VERSION 5.7 ;
  NOWIREEXTENSIONATPIN ON ;
  DIVIDERCHAR "/" ;
  BUSBITCHARS "[]" ;
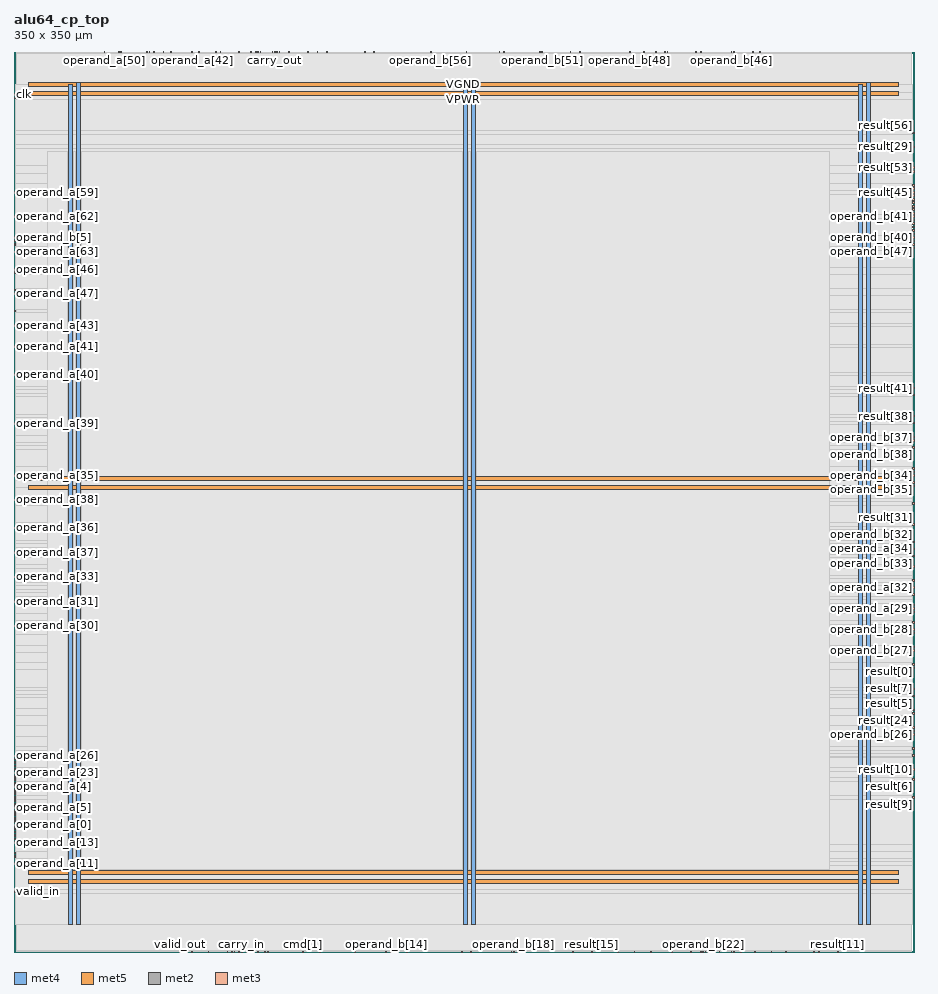
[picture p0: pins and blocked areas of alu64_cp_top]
MACRO alu64_cp_top
  CLASS BLOCK ;
  FOREIGN alu64_cp_top ;
  ORIGIN 0.000 0.000 ;
  SIZE 350.000 BY 350.000 ;
  PIN VGND
    DIRECTION INOUT ;
    USE GROUND ;
    PORT
      LAYER met4 ;
        RECT 24.340 10.640 25.940 337.990 ;
    END
    PORT
      LAYER met4 ;
        RECT 177.940 10.640 179.540 337.990 ;
    END
    PORT
      LAYER met4 ;
        RECT 331.540 10.640 333.140 337.990 ;
    END
    PORT
      LAYER met5 ;
        RECT 5.520 30.030 344.080 31.630 ;
    END
    PORT
      LAYER met5 ;
        RECT 5.520 183.210 344.080 184.810 ;
    END
    PORT
      LAYER met5 ;
        RECT 5.520 336.390 344.080 337.990 ;
    END
  END VGND
  PIN VPWR
    DIRECTION INOUT ;
    USE POWER ;
    PORT
      LAYER met4 ;
        RECT 21.040 10.640 22.640 337.520 ;
    END
    PORT
      LAYER met4 ;
        RECT 174.640 10.640 176.240 337.520 ;
    END
    PORT
      LAYER met4 ;
        RECT 328.240 10.640 329.840 337.520 ;
    END
    PORT
      LAYER met5 ;
        RECT 5.520 26.730 344.080 28.330 ;
    END
    PORT
      LAYER met5 ;
        RECT 5.520 179.910 344.080 181.510 ;
    END
    PORT
      LAYER met5 ;
        RECT 5.520 333.090 344.080 334.690 ;
    END
  END VPWR
  PIN carry_in
    DIRECTION INPUT ;
    USE SIGNAL ;
    ANTENNAGATEAREA 0.213000 ;
    PORT
      LAYER met2 ;
        RECT 88.410 0.000 88.690 0.280 ;
    END
  END carry_in
  PIN carry_out
    DIRECTION OUTPUT ;
    USE SIGNAL ;
    ANTENNADIFFAREA 0.702900 ;
    PORT
      LAYER met2 ;
        RECT 101.290 349.720 101.570 350.000 ;
    END
  END carry_out
  PIN clk
    DIRECTION INPUT ;
    USE SIGNAL ;
    ANTENNAGATEAREA 0.852000 ;
    PORT
      LAYER met3 ;
        RECT 0.000 333.240 0.600 333.840 ;
    END
  END clk
  PIN cmd[0]
    DIRECTION INPUT ;
    USE SIGNAL ;
    ANTENNAGATEAREA 0.213000 ;
    PORT
      LAYER met2 ;
        RECT 97.610 0.000 97.890 0.280 ;
    END
  END cmd[0]
  PIN cmd[1]
    DIRECTION INPUT ;
    USE SIGNAL ;
    ANTENNAGATEAREA 0.213000 ;
    PORT
      LAYER met2 ;
        RECT 112.330 0.000 112.610 0.280 ;
    END
  END cmd[1]
  PIN cmd[2]
    DIRECTION INPUT ;
    USE SIGNAL ;
    ANTENNAGATEAREA 0.213000 ;
    PORT
      LAYER met2 ;
        RECT 100.370 349.720 100.650 350.000 ;
    END
  END cmd[2]
  PIN cmd[3]
    DIRECTION INPUT ;
    USE SIGNAL ;
    ANTENNAGATEAREA 0.213000 ;
    PORT
      LAYER met2 ;
        RECT 93.930 349.720 94.210 350.000 ;
    END
  END cmd[3]
  PIN negative_flag
    DIRECTION OUTPUT ;
    USE SIGNAL ;
    ANTENNADIFFAREA 0.702900 ;
    PORT
      LAYER met3 ;
        RECT 349.400 296.520 350.000 297.120 ;
    END
  END negative_flag
  PIN operand_a[0]
    DIRECTION INPUT ;
    USE SIGNAL ;
    ANTENNAGATEAREA 0.213000 ;
    PORT
      LAYER met3 ;
        RECT 0.000 46.280 0.600 46.880 ;
    END
  END operand_a[0]
  PIN operand_a[10]
    DIRECTION INPUT ;
    USE SIGNAL ;
    ANTENNAGATEAREA 0.213000 ;
    PORT
      LAYER met3 ;
        RECT 0.000 51.720 0.600 52.320 ;
    END
  END operand_a[10]
  PIN operand_a[11]
    DIRECTION INPUT ;
    USE SIGNAL ;
    ANTENNAGATEAREA 0.213000 ;
    PORT
      LAYER met3 ;
        RECT 0.000 36.760 0.600 37.360 ;
    END
  END operand_a[11]
  PIN operand_a[12]
    DIRECTION INPUT ;
    USE SIGNAL ;
    ANTENNAGATEAREA 0.213000 ;
    PORT
      LAYER met3 ;
        RECT 0.000 34.040 0.600 34.640 ;
    END
  END operand_a[12]
  PIN operand_a[13]
    DIRECTION INPUT ;
    USE SIGNAL ;
    ANTENNAGATEAREA 0.213000 ;
    PORT
      LAYER met3 ;
        RECT 0.000 42.200 0.600 42.800 ;
    END
  END operand_a[13]
  PIN operand_a[14]
    DIRECTION INPUT ;
    USE SIGNAL ;
    ANTENNAGATEAREA 0.213000 ;
    PORT
      LAYER met3 ;
        RECT 0.000 54.440 0.600 55.040 ;
    END
  END operand_a[14]
  PIN operand_a[15]
    DIRECTION INPUT ;
    USE SIGNAL ;
    ANTENNAGATEAREA 0.213000 ;
    PORT
      LAYER met3 ;
        RECT 0.000 57.160 0.600 57.760 ;
    END
  END operand_a[15]
  PIN operand_a[16]
    DIRECTION INPUT ;
    USE SIGNAL ;
    ANTENNAGATEAREA 0.213000 ;
    PORT
      LAYER met3 ;
        RECT 0.000 38.120 0.600 38.720 ;
    END
  END operand_a[16]
  PIN operand_a[17]
    DIRECTION INPUT ;
    USE SIGNAL ;
    ANTENNAGATEAREA 0.213000 ;
    PORT
      LAYER met3 ;
        RECT 0.000 49.000 0.600 49.600 ;
    END
  END operand_a[17]
  PIN operand_a[18]
    DIRECTION INPUT ;
    USE SIGNAL ;
    ANTENNAGATEAREA 0.213000 ;
    PORT
      LAYER met3 ;
        RECT 0.000 53.080 0.600 53.680 ;
    END
  END operand_a[18]
  PIN operand_a[19]
    DIRECTION INPUT ;
    USE SIGNAL ;
    ANTENNAGATEAREA 0.213000 ;
    PORT
      LAYER met3 ;
        RECT 0.000 43.560 0.600 44.160 ;
    END
  END operand_a[19]
  PIN operand_a[1]
    DIRECTION INPUT ;
    USE SIGNAL ;
    ANTENNAGATEAREA 0.213000 ;
    PORT
      LAYER met2 ;
        RECT 69.090 0.000 69.370 0.280 ;
    END
  END operand_a[1]
  PIN operand_a[20]
    DIRECTION INPUT ;
    USE SIGNAL ;
    ANTENNAGATEAREA 0.213000 ;
    PORT
      LAYER met3 ;
        RECT 0.000 44.920 0.600 45.520 ;
    END
  END operand_a[20]
  PIN operand_a[21]
    DIRECTION INPUT ;
    USE SIGNAL ;
    ANTENNAGATEAREA 0.213000 ;
    PORT
      LAYER met3 ;
        RECT 0.000 61.240 0.600 61.840 ;
    END
  END operand_a[21]
  PIN operand_a[22]
    DIRECTION INPUT ;
    USE SIGNAL ;
    ANTENNAGATEAREA 0.213000 ;
    PORT
      LAYER met3 ;
        RECT 0.000 63.960 0.600 64.560 ;
    END
  END operand_a[22]
  PIN operand_a[23]
    DIRECTION INPUT ;
    USE SIGNAL ;
    ANTENNAGATEAREA 0.213000 ;
    PORT
      LAYER met3 ;
        RECT 0.000 69.400 0.600 70.000 ;
    END
  END operand_a[23]
  PIN operand_a[24]
    DIRECTION INPUT ;
    USE SIGNAL ;
    ANTENNAGATEAREA 0.213000 ;
    PORT
      LAYER met3 ;
        RECT 0.000 70.760 0.600 71.360 ;
    END
  END operand_a[24]
  PIN operand_a[25]
    DIRECTION INPUT ;
    USE SIGNAL ;
    ANTENNAGATEAREA 0.213000 ;
    PORT
      LAYER met2 ;
        RECT 75.530 0.000 75.810 0.280 ;
    END
  END operand_a[25]
  PIN operand_a[26]
    DIRECTION INPUT ;
    USE SIGNAL ;
    ANTENNAGATEAREA 0.213000 ;
    PORT
      LAYER met3 ;
        RECT 0.000 73.480 0.600 74.080 ;
    END
  END operand_a[26]
  PIN operand_a[27]
    DIRECTION INPUT ;
    USE SIGNAL ;
    ANTENNAGATEAREA 0.213000 ;
    PORT
      LAYER met3 ;
        RECT 0.000 47.640 0.600 48.240 ;
    END
  END operand_a[27]
  PIN operand_a[28]
    DIRECTION INPUT ;
    USE SIGNAL ;
    ANTENNAGATEAREA 0.213000 ;
    PORT
      LAYER met3 ;
        RECT 0.000 74.840 0.600 75.440 ;
    END
  END operand_a[28]
  PIN operand_a[29]
    DIRECTION INPUT ;
    USE SIGNAL ;
    ANTENNAGATEAREA 0.213000 ;
    PORT
      LAYER met3 ;
        RECT 349.400 133.320 350.000 133.920 ;
    END
  END operand_a[29]
  PIN operand_a[2]
    DIRECTION INPUT ;
    USE SIGNAL ;
    ANTENNAGATEAREA 0.213000 ;
    PORT
      LAYER met3 ;
        RECT 0.000 68.040 0.600 68.640 ;
    END
  END operand_a[2]
  PIN operand_a[30]
    DIRECTION INPUT ;
    USE SIGNAL ;
    ANTENNAGATEAREA 0.213000 ;
    PORT
      LAYER met3 ;
        RECT 0.000 126.520 0.600 127.120 ;
    END
  END operand_a[30]
  PIN operand_a[31]
    DIRECTION INPUT ;
    USE SIGNAL ;
    ANTENNAGATEAREA 0.213000 ;
    PORT
      LAYER met3 ;
        RECT 0.000 136.040 0.600 136.640 ;
    END
  END operand_a[31]
  PIN operand_a[32]
    DIRECTION INPUT ;
    USE SIGNAL ;
    ANTENNAGATEAREA 0.213000 ;
    PORT
      LAYER met3 ;
        RECT 349.400 141.480 350.000 142.080 ;
    END
  END operand_a[32]
  PIN operand_a[33]
    DIRECTION INPUT ;
    USE SIGNAL ;
    ANTENNAGATEAREA 0.213000 ;
    PORT
      LAYER met3 ;
        RECT 0.000 145.560 0.600 146.160 ;
    END
  END operand_a[33]
  PIN operand_a[34]
    DIRECTION INPUT ;
    USE SIGNAL ;
    ANTENNAGATEAREA 0.213000 ;
    PORT
      LAYER met3 ;
        RECT 349.400 156.440 350.000 157.040 ;
    END
  END operand_a[34]
  PIN operand_a[35]
    DIRECTION INPUT ;
    USE SIGNAL ;
    ANTENNAGATEAREA 0.213000 ;
    PORT
      LAYER met3 ;
        RECT 0.000 185.000 0.600 185.600 ;
    END
  END operand_a[35]
  PIN operand_a[36]
    DIRECTION INPUT ;
    USE SIGNAL ;
    ANTENNAGATEAREA 0.213000 ;
    PORT
      LAYER met3 ;
        RECT 0.000 164.600 0.600 165.200 ;
    END
  END operand_a[36]
  PIN operand_a[37]
    DIRECTION INPUT ;
    USE SIGNAL ;
    ANTENNAGATEAREA 0.213000 ;
    PORT
      LAYER met3 ;
        RECT 0.000 155.080 0.600 155.680 ;
    END
  END operand_a[37]
  PIN operand_a[38]
    DIRECTION INPUT ;
    USE SIGNAL ;
    ANTENNAGATEAREA 0.213000 ;
    PORT
      LAYER met3 ;
        RECT 0.000 175.480 0.600 176.080 ;
    END
  END operand_a[38]
  PIN operand_a[39]
    DIRECTION INPUT ;
    USE SIGNAL ;
    ANTENNAGATEAREA 0.213000 ;
    PORT
      LAYER met3 ;
        RECT 0.000 205.400 0.600 206.000 ;
    END
  END operand_a[39]
  PIN operand_a[3]
    DIRECTION INPUT ;
    USE SIGNAL ;
    ANTENNAGATEAREA 0.213000 ;
    PORT
      LAYER met3 ;
        RECT 0.000 72.120 0.600 72.720 ;
    END
  END operand_a[3]
  PIN operand_a[40]
    DIRECTION INPUT ;
    USE SIGNAL ;
    ANTENNAGATEAREA 0.213000 ;
    PORT
      LAYER met3 ;
        RECT 0.000 224.440 0.600 225.040 ;
    END
  END operand_a[40]
  PIN operand_a[41]
    DIRECTION INPUT ;
    USE SIGNAL ;
    ANTENNAGATEAREA 0.213000 ;
    PORT
      LAYER met3 ;
        RECT 0.000 235.320 0.600 235.920 ;
    END
  END operand_a[41]
  PIN operand_a[42]
    DIRECTION INPUT ;
    USE SIGNAL ;
    ANTENNAGATEAREA 0.213000 ;
    PORT
      LAYER met2 ;
        RECT 69.090 349.720 69.370 350.000 ;
    END
  END operand_a[42]
  PIN operand_a[43]
    DIRECTION INPUT ;
    USE SIGNAL ;
    ANTENNAGATEAREA 0.213000 ;
    PORT
      LAYER met3 ;
        RECT 0.000 243.480 0.600 244.080 ;
    END
  END operand_a[43]
  PIN operand_a[44]
    DIRECTION INPUT ;
    USE SIGNAL ;
    ANTENNAGATEAREA 0.213000 ;
    PORT
      LAYER met2 ;
        RECT 58.050 349.720 58.330 350.000 ;
    END
  END operand_a[44]
  PIN operand_a[45]
    DIRECTION INPUT ;
    USE SIGNAL ;
    ANTENNAGATEAREA 0.213000 ;
    PORT
      LAYER met3 ;
        RECT 0.000 257.080 0.600 257.680 ;
    END
  END operand_a[45]
  PIN operand_a[46]
    DIRECTION INPUT ;
    USE SIGNAL ;
    ANTENNAGATEAREA 0.213000 ;
    PORT
      LAYER met3 ;
        RECT 0.000 265.240 0.600 265.840 ;
    END
  END operand_a[46]
  PIN operand_a[47]
    DIRECTION INPUT ;
    USE SIGNAL ;
    ANTENNAGATEAREA 0.213000 ;
    PORT
      LAYER met3 ;
        RECT 0.000 255.720 0.600 256.320 ;
    END
  END operand_a[47]
  PIN operand_a[48]
    DIRECTION INPUT ;
    USE SIGNAL ;
    ANTENNAGATEAREA 0.213000 ;
    PORT
      LAYER met2 ;
        RECT 60.810 349.720 61.090 350.000 ;
    END
  END operand_a[48]
  PIN operand_a[49]
    DIRECTION INPUT ;
    USE SIGNAL ;
    ANTENNAGATEAREA 0.213000 ;
    PORT
      LAYER met2 ;
        RECT 71.850 349.720 72.130 350.000 ;
    END
  END operand_a[49]
  PIN operand_a[4]
    DIRECTION INPUT ;
    USE SIGNAL ;
    ANTENNAGATEAREA 0.213000 ;
    PORT
      LAYER met3 ;
        RECT 0.000 66.680 0.600 67.280 ;
    END
  END operand_a[4]
  PIN operand_a[50]
    DIRECTION INPUT ;
    USE SIGNAL ;
    ANTENNAGATEAREA 0.213000 ;
    PORT
      LAYER met2 ;
        RECT 35.050 349.720 35.330 350.000 ;
    END
  END operand_a[50]
  PIN operand_a[51]
    DIRECTION INPUT ;
    USE SIGNAL ;
    ANTENNAGATEAREA 0.213000 ;
    PORT
      LAYER met2 ;
        RECT 52.530 349.720 52.810 350.000 ;
    END
  END operand_a[51]
  PIN operand_a[52]
    DIRECTION INPUT ;
    USE SIGNAL ;
    ANTENNAGATEAREA 0.213000 ;
    PORT
      LAYER met2 ;
        RECT 41.490 349.720 41.770 350.000 ;
    END
  END operand_a[52]
  PIN operand_a[53]
    DIRECTION INPUT ;
    USE SIGNAL ;
    ANTENNAGATEAREA 0.213000 ;
    PORT
      LAYER met2 ;
        RECT 80.130 349.720 80.410 350.000 ;
    END
  END operand_a[53]
  PIN operand_a[54]
    DIRECTION INPUT ;
    USE SIGNAL ;
    ANTENNAGATEAREA 0.213000 ;
    PORT
      LAYER met2 ;
        RECT 87.490 349.720 87.770 350.000 ;
    END
  END operand_a[54]
  PIN operand_a[55]
    DIRECTION INPUT ;
    USE SIGNAL ;
    ANTENNAGATEAREA 0.213000 ;
    PORT
      LAYER met2 ;
        RECT 78.290 349.720 78.570 350.000 ;
    END
  END operand_a[55]
  PIN operand_a[56]
    DIRECTION INPUT ;
    USE SIGNAL ;
    ANTENNAGATEAREA 0.213000 ;
    PORT
      LAYER met2 ;
        RECT 95.770 349.720 96.050 350.000 ;
    END
  END operand_a[56]
  PIN operand_a[57]
    DIRECTION INPUT ;
    USE SIGNAL ;
    ANTENNAGATEAREA 0.213000 ;
    PORT
      LAYER met2 ;
        RECT 92.090 349.720 92.370 350.000 ;
    END
  END operand_a[57]
  PIN operand_a[58]
    DIRECTION INPUT ;
    USE SIGNAL ;
    ANTENNAGATEAREA 0.213000 ;
    PORT
      LAYER met2 ;
        RECT 94.850 349.720 95.130 350.000 ;
    END
  END operand_a[58]
  PIN operand_a[59]
    DIRECTION INPUT ;
    USE SIGNAL ;
    ANTENNAGATEAREA 0.213000 ;
    PORT
      LAYER met3 ;
        RECT 0.000 295.160 0.600 295.760 ;
    END
  END operand_a[59]
  PIN operand_a[5]
    DIRECTION INPUT ;
    USE SIGNAL ;
    ANTENNAGATEAREA 0.213000 ;
    PORT
      LAYER met3 ;
        RECT 0.000 58.520 0.600 59.120 ;
    END
  END operand_a[5]
  PIN operand_a[60]
    DIRECTION INPUT ;
    USE SIGNAL ;
    ANTENNAGATEAREA 0.213000 ;
    PORT
      LAYER met2 ;
        RECT 54.370 349.720 54.650 350.000 ;
    END
  END operand_a[60]
  PIN operand_a[61]
    DIRECTION INPUT ;
    USE SIGNAL ;
    ANTENNAGATEAREA 0.213000 ;
    PORT
      LAYER met2 ;
        RECT 51.610 349.720 51.890 350.000 ;
    END
  END operand_a[61]
  PIN operand_a[62]
    DIRECTION INPUT ;
    USE SIGNAL ;
    ANTENNAGATEAREA 0.213000 ;
    PORT
      LAYER met3 ;
        RECT 0.000 285.640 0.600 286.240 ;
    END
  END operand_a[62]
  PIN operand_a[63]
    DIRECTION INPUT ;
    USE SIGNAL ;
    ANTENNAGATEAREA 0.213000 ;
    PORT
      LAYER met3 ;
        RECT 0.000 274.760 0.600 275.360 ;
    END
  END operand_a[63]
  PIN operand_a[6]
    DIRECTION INPUT ;
    USE SIGNAL ;
    ANTENNAGATEAREA 0.213000 ;
    PORT
      LAYER met3 ;
        RECT 0.000 65.320 0.600 65.920 ;
    END
  END operand_a[6]
  PIN operand_a[7]
    DIRECTION INPUT ;
    USE SIGNAL ;
    ANTENNAGATEAREA 0.213000 ;
    PORT
      LAYER met3 ;
        RECT 0.000 50.360 0.600 50.960 ;
    END
  END operand_a[7]
  PIN operand_a[8]
    DIRECTION INPUT ;
    USE SIGNAL ;
    ANTENNAGATEAREA 0.213000 ;
    PORT
      LAYER met3 ;
        RECT 0.000 59.880 0.600 60.480 ;
    END
  END operand_a[8]
  PIN operand_a[9]
    DIRECTION INPUT ;
    USE SIGNAL ;
    ANTENNAGATEAREA 0.213000 ;
    PORT
      LAYER met3 ;
        RECT 0.000 62.600 0.600 63.200 ;
    END
  END operand_a[9]
  PIN operand_b[0]
    DIRECTION INPUT ;
    USE SIGNAL ;
    ANTENNAGATEAREA 0.213000 ;
    PORT
      LAYER met3 ;
        RECT 0.000 55.800 0.600 56.400 ;
    END
  END operand_b[0]
  PIN operand_b[10]
    DIRECTION INPUT ;
    USE SIGNAL ;
    ANTENNAGATEAREA 0.213000 ;
    PORT
      LAYER met2 ;
        RECT 98.530 0.000 98.810 0.280 ;
    END
  END operand_b[10]
  PIN operand_b[11]
    DIRECTION INPUT ;
    USE SIGNAL ;
    ANTENNAGATEAREA 0.213000 ;
    PORT
      LAYER met2 ;
        RECT 94.850 0.000 95.130 0.280 ;
    END
  END operand_b[11]
  PIN operand_b[12]
    DIRECTION INPUT ;
    USE SIGNAL ;
    ANTENNAGATEAREA 0.213000 ;
    PORT
      LAYER met2 ;
        RECT 118.770 0.000 119.050 0.280 ;
    END
  END operand_b[12]
  PIN operand_b[13]
    DIRECTION INPUT ;
    USE SIGNAL ;
    ANTENNAGATEAREA 0.213000 ;
    PORT
      LAYER met2 ;
        RECT 132.570 0.000 132.850 0.280 ;
    END
  END operand_b[13]
  PIN operand_b[14]
    DIRECTION INPUT ;
    USE SIGNAL ;
    ANTENNAGATEAREA 0.213000 ;
    PORT
      LAYER met2 ;
        RECT 144.530 0.000 144.810 0.280 ;
    END
  END operand_b[14]
  PIN operand_b[15]
    DIRECTION INPUT ;
    USE SIGNAL ;
    ANTENNAGATEAREA 0.213000 ;
    PORT
      LAYER met2 ;
        RECT 149.130 0.000 149.410 0.280 ;
    END
  END operand_b[15]
  PIN operand_b[16]
    DIRECTION INPUT ;
    USE SIGNAL ;
    ANTENNAGATEAREA 0.213000 ;
    PORT
      LAYER met2 ;
        RECT 152.810 0.000 153.090 0.280 ;
    END
  END operand_b[16]
  PIN operand_b[17]
    DIRECTION INPUT ;
    USE SIGNAL ;
    ANTENNAGATEAREA 0.213000 ;
    PORT
      LAYER met2 ;
        RECT 173.970 0.000 174.250 0.280 ;
    END
  END operand_b[17]
  PIN operand_b[18]
    DIRECTION INPUT ;
    USE SIGNAL ;
    ANTENNAGATEAREA 0.213000 ;
    PORT
      LAYER met2 ;
        RECT 194.210 0.000 194.490 0.280 ;
    END
  END operand_b[18]
  PIN operand_b[19]
    DIRECTION INPUT ;
    USE SIGNAL ;
    ANTENNAGATEAREA 0.213000 ;
    PORT
      LAYER met2 ;
        RECT 217.210 0.000 217.490 0.280 ;
    END
  END operand_b[19]
  PIN operand_b[1]
    DIRECTION INPUT ;
    USE SIGNAL ;
    ANTENNAGATEAREA 0.213000 ;
    PORT
      LAYER met3 ;
        RECT 0.000 263.880 0.600 264.480 ;
    END
  END operand_b[1]
  PIN operand_b[20]
    DIRECTION INPUT ;
    USE SIGNAL ;
    ANTENNAGATEAREA 0.213000 ;
    PORT
      LAYER met2 ;
        RECT 241.130 0.000 241.410 0.280 ;
    END
  END operand_b[20]
  PIN operand_b[21]
    DIRECTION INPUT ;
    USE SIGNAL ;
    ANTENNAGATEAREA 0.213000 ;
    PORT
      LAYER met2 ;
        RECT 255.850 0.000 256.130 0.280 ;
    END
  END operand_b[21]
  PIN operand_b[22]
    DIRECTION INPUT ;
    USE SIGNAL ;
    ANTENNAGATEAREA 0.213000 ;
    PORT
      LAYER met2 ;
        RECT 267.810 0.000 268.090 0.280 ;
    END
  END operand_b[22]
  PIN operand_b[23]
    DIRECTION INPUT ;
    USE SIGNAL ;
    ANTENNAGATEAREA 0.213000 ;
    PORT
      LAYER met2 ;
        RECT 278.850 0.000 279.130 0.280 ;
    END
  END operand_b[23]
  PIN operand_b[24]
    DIRECTION INPUT ;
    USE SIGNAL ;
    ANTENNAGATEAREA 0.213000 ;
    PORT
      LAYER met2 ;
        RECT 282.530 0.000 282.810 0.280 ;
    END
  END operand_b[24]
  PIN operand_b[25]
    DIRECTION INPUT ;
    USE SIGNAL ;
    ANTENNAGATEAREA 0.213000 ;
    PORT
      LAYER met2 ;
        RECT 274.250 0.000 274.530 0.280 ;
    END
  END operand_b[25]
  PIN operand_b[26]
    DIRECTION INPUT ;
    USE SIGNAL ;
    ANTENNAGATEAREA 0.213000 ;
    PORT
      LAYER met3 ;
        RECT 349.400 84.360 350.000 84.960 ;
    END
  END operand_b[26]
  PIN operand_b[27]
    DIRECTION INPUT ;
    USE SIGNAL ;
    ANTENNAGATEAREA 0.213000 ;
    PORT
      LAYER met3 ;
        RECT 349.400 117.000 350.000 117.600 ;
    END
  END operand_b[27]
  PIN operand_b[28]
    DIRECTION INPUT ;
    USE SIGNAL ;
    ANTENNAGATEAREA 0.213000 ;
    PORT
      LAYER met3 ;
        RECT 349.400 127.880 350.000 128.480 ;
    END
  END operand_b[28]
  PIN operand_b[29]
    DIRECTION INPUT ;
    USE SIGNAL ;
    ANTENNAGATEAREA 0.213000 ;
    PORT
      LAYER met3 ;
        RECT 349.400 131.960 350.000 132.560 ;
    END
  END operand_b[29]
  PIN operand_b[2]
    DIRECTION INPUT ;
    USE SIGNAL ;
    ANTENNAGATEAREA 0.213000 ;
    PORT
      LAYER met3 ;
        RECT 0.000 276.120 0.600 276.720 ;
    END
  END operand_b[2]
  PIN operand_b[30]
    DIRECTION INPUT ;
    USE SIGNAL ;
    ANTENNAGATEAREA 0.213000 ;
    PORT
      LAYER met3 ;
        RECT 349.400 123.800 350.000 124.400 ;
    END
  END operand_b[30]
  PIN operand_b[31]
    DIRECTION INPUT ;
    USE SIGNAL ;
    ANTENNAGATEAREA 0.213000 ;
    PORT
      LAYER met3 ;
        RECT 349.400 134.680 350.000 135.280 ;
    END
  END operand_b[31]
  PIN operand_b[32]
    DIRECTION INPUT ;
    USE SIGNAL ;
    ANTENNAGATEAREA 0.213000 ;
    PORT
      LAYER met3 ;
        RECT 349.400 159.160 350.000 159.760 ;
    END
  END operand_b[32]
  PIN operand_b[33]
    DIRECTION INPUT ;
    USE SIGNAL ;
    ANTENNAGATEAREA 0.213000 ;
    PORT
      LAYER met3 ;
        RECT 349.400 153.720 350.000 154.320 ;
    END
  END operand_b[33]
  PIN operand_b[34]
    DIRECTION INPUT ;
    USE SIGNAL ;
    ANTENNAGATEAREA 0.213000 ;
    PORT
      LAYER met3 ;
        RECT 349.400 185.000 350.000 185.600 ;
    END
  END operand_b[34]
  PIN operand_b[35]
    DIRECTION INPUT ;
    USE SIGNAL ;
    ANTENNAGATEAREA 0.213000 ;
    PORT
      LAYER met3 ;
        RECT 349.400 182.280 350.000 182.880 ;
    END
  END operand_b[35]
  PIN operand_b[36]
    DIRECTION INPUT ;
    USE SIGNAL ;
    ANTENNAGATEAREA 0.213000 ;
    PORT
      LAYER met3 ;
        RECT 349.400 186.360 350.000 186.960 ;
    END
  END operand_b[36]
  PIN operand_b[37]
    DIRECTION INPUT ;
    USE SIGNAL ;
    ANTENNAGATEAREA 0.213000 ;
    PORT
      LAYER met3 ;
        RECT 349.400 199.960 350.000 200.560 ;
    END
  END operand_b[37]
  PIN operand_b[38]
    DIRECTION INPUT ;
    USE SIGNAL ;
    ANTENNAGATEAREA 0.213000 ;
    PORT
      LAYER met3 ;
        RECT 349.400 195.880 350.000 196.480 ;
    END
  END operand_b[38]
  PIN operand_b[39]
    DIRECTION INPUT ;
    USE SIGNAL ;
    ANTENNAGATEAREA 0.213000 ;
    PORT
      LAYER met3 ;
        RECT 349.400 187.720 350.000 188.320 ;
    END
  END operand_b[39]
  PIN operand_b[3]
    DIRECTION INPUT ;
    USE SIGNAL ;
    ANTENNAGATEAREA 0.213000 ;
    PORT
      LAYER met3 ;
        RECT 0.000 248.920 0.600 249.520 ;
    END
  END operand_b[3]
  PIN operand_b[40]
    DIRECTION INPUT ;
    USE SIGNAL ;
    ANTENNAGATEAREA 0.213000 ;
    PORT
      LAYER met3 ;
        RECT 349.400 277.480 350.000 278.080 ;
    END
  END operand_b[40]
  PIN operand_b[41]
    DIRECTION INPUT ;
    USE SIGNAL ;
    ANTENNAGATEAREA 0.213000 ;
    PORT
      LAYER met3 ;
        RECT 349.400 282.920 350.000 283.520 ;
    END
  END operand_b[41]
  PIN operand_b[42]
    DIRECTION INPUT ;
    USE SIGNAL ;
    ANTENNAGATEAREA 0.213000 ;
    PORT
      LAYER met3 ;
        RECT 349.400 276.120 350.000 276.720 ;
    END
  END operand_b[42]
  PIN operand_b[43]
    DIRECTION INPUT ;
    USE SIGNAL ;
    ANTENNAGATEAREA 0.213000 ;
    PORT
      LAYER met3 ;
        RECT 349.400 291.080 350.000 291.680 ;
    END
  END operand_b[43]
  PIN operand_b[44]
    DIRECTION INPUT ;
    USE SIGNAL ;
    ANTENNAGATEAREA 0.213000 ;
    PORT
      LAYER met3 ;
        RECT 349.400 292.440 350.000 293.040 ;
    END
  END operand_b[44]
  PIN operand_b[45]
    DIRECTION INPUT ;
    USE SIGNAL ;
    ANTENNAGATEAREA 0.213000 ;
    PORT
      LAYER met3 ;
        RECT 349.400 285.640 350.000 286.240 ;
    END
  END operand_b[45]
  PIN operand_b[46]
    DIRECTION INPUT ;
    USE SIGNAL ;
    ANTENNAGATEAREA 0.213000 ;
    PORT
      LAYER met2 ;
        RECT 278.850 349.720 279.130 350.000 ;
    END
  END operand_b[46]
  PIN operand_b[47]
    DIRECTION INPUT ;
    USE SIGNAL ;
    ANTENNAGATEAREA 0.213000 ;
    PORT
      LAYER met3 ;
        RECT 349.400 274.760 350.000 275.360 ;
    END
  END operand_b[47]
  PIN operand_b[48]
    DIRECTION INPUT ;
    USE SIGNAL ;
    ANTENNAGATEAREA 0.213000 ;
    PORT
      LAYER met2 ;
        RECT 239.290 349.720 239.570 350.000 ;
    END
  END operand_b[48]
  PIN operand_b[49]
    DIRECTION INPUT ;
    USE SIGNAL ;
    ANTENNAGATEAREA 0.213000 ;
    PORT
      LAYER met2 ;
        RECT 219.970 349.720 220.250 350.000 ;
    END
  END operand_b[49]
  PIN operand_b[4]
    DIRECTION INPUT ;
    USE SIGNAL ;
    ANTENNAGATEAREA 0.213000 ;
    PORT
      LAYER met2 ;
        RECT 40.570 349.720 40.850 350.000 ;
    END
  END operand_b[4]
  PIN operand_b[50]
    DIRECTION INPUT ;
    USE SIGNAL ;
    ANTENNAGATEAREA 0.213000 ;
    PORT
      LAYER met2 ;
        RECT 216.290 349.720 216.570 350.000 ;
    END
  END operand_b[50]
  PIN operand_b[51]
    DIRECTION INPUT ;
    USE SIGNAL ;
    ANTENNAGATEAREA 0.213000 ;
    PORT
      LAYER met2 ;
        RECT 205.250 349.720 205.530 350.000 ;
    END
  END operand_b[51]
  PIN operand_b[52]
    DIRECTION INPUT ;
    USE SIGNAL ;
    ANTENNAGATEAREA 0.213000 ;
    PORT
      LAYER met2 ;
        RECT 204.330 349.720 204.610 350.000 ;
    END
  END operand_b[52]
  PIN operand_b[53]
    DIRECTION INPUT ;
    USE SIGNAL ;
    ANTENNAGATEAREA 0.213000 ;
    PORT
      LAYER met2 ;
        RECT 188.690 349.720 188.970 350.000 ;
    END
  END operand_b[53]
  PIN operand_b[54]
    DIRECTION INPUT ;
    USE SIGNAL ;
    ANTENNAGATEAREA 0.213000 ;
    PORT
      LAYER met2 ;
        RECT 190.530 349.720 190.810 350.000 ;
    END
  END operand_b[54]
  PIN operand_b[55]
    DIRECTION INPUT ;
    USE SIGNAL ;
    ANTENNAGATEAREA 0.213000 ;
    PORT
      LAYER met2 ;
        RECT 175.810 349.720 176.090 350.000 ;
    END
  END operand_b[55]
  PIN operand_b[56]
    DIRECTION INPUT ;
    USE SIGNAL ;
    ANTENNAGATEAREA 0.213000 ;
    PORT
      LAYER met2 ;
        RECT 162.010 349.720 162.290 350.000 ;
    END
  END operand_b[56]
  PIN operand_b[57]
    DIRECTION INPUT ;
    USE SIGNAL ;
    ANTENNAGATEAREA 0.213000 ;
    PORT
      LAYER met2 ;
        RECT 139.930 349.720 140.210 350.000 ;
    END
  END operand_b[57]
  PIN operand_b[58]
    DIRECTION INPUT ;
    USE SIGNAL ;
    ANTENNAGATEAREA 0.213000 ;
    PORT
      LAYER met2 ;
        RECT 136.250 349.720 136.530 350.000 ;
    END
  END operand_b[58]
  PIN operand_b[59]
    DIRECTION INPUT ;
    USE SIGNAL ;
    ANTENNAGATEAREA 0.213000 ;
    PORT
      LAYER met2 ;
        RECT 117.850 349.720 118.130 350.000 ;
    END
  END operand_b[59]
  PIN operand_b[5]
    DIRECTION INPUT ;
    USE SIGNAL ;
    ANTENNAGATEAREA 0.213000 ;
    PORT
      LAYER met3 ;
        RECT 0.000 277.480 0.600 278.080 ;
    END
  END operand_b[5]
  PIN operand_b[60]
    DIRECTION INPUT ;
    USE SIGNAL ;
    ANTENNAGATEAREA 0.213000 ;
    PORT
      LAYER met2 ;
        RECT 114.170 349.720 114.450 350.000 ;
    END
  END operand_b[60]
  PIN operand_b[61]
    DIRECTION INPUT ;
    USE SIGNAL ;
    ANTENNAGATEAREA 0.213000 ;
    PORT
      LAYER met2 ;
        RECT 106.810 349.720 107.090 350.000 ;
    END
  END operand_b[61]
  PIN operand_b[62]
    DIRECTION INPUT ;
    USE SIGNAL ;
    ANTENNAGATEAREA 0.213000 ;
    PORT
      LAYER met2 ;
        RECT 103.130 349.720 103.410 350.000 ;
    END
  END operand_b[62]
  PIN operand_b[63]
    DIRECTION INPUT ;
    USE SIGNAL ;
    ANTENNAGATEAREA 0.213000 ;
    PORT
      LAYER met2 ;
        RECT 102.210 349.720 102.490 350.000 ;
    END
  END operand_b[63]
  PIN operand_b[6]
    DIRECTION INPUT ;
    USE SIGNAL ;
    ANTENNAGATEAREA 0.213000 ;
    PORT
      LAYER met2 ;
        RECT 82.890 0.000 83.170 0.280 ;
    END
  END operand_b[6]
  PIN operand_b[7]
    DIRECTION INPUT ;
    USE SIGNAL ;
    ANTENNAGATEAREA 0.213000 ;
    PORT
      LAYER met2 ;
        RECT 85.650 0.000 85.930 0.280 ;
    END
  END operand_b[7]
  PIN operand_b[8]
    DIRECTION INPUT ;
    USE SIGNAL ;
    ANTENNAGATEAREA 0.213000 ;
    PORT
      LAYER met2 ;
        RECT 84.730 0.000 85.010 0.280 ;
    END
  END operand_b[8]
  PIN operand_b[9]
    DIRECTION INPUT ;
    USE SIGNAL ;
    ANTENNAGATEAREA 0.213000 ;
    PORT
      LAYER met2 ;
        RECT 87.490 0.000 87.770 0.280 ;
    END
  END operand_b[9]
  PIN overflow_flag
    DIRECTION OUTPUT ;
    USE SIGNAL ;
    ANTENNADIFFAREA 0.702900 ;
    PORT
      LAYER met2 ;
        RECT 121.530 349.720 121.810 350.000 ;
    END
  END overflow_flag
  PIN result[0]
    DIRECTION OUTPUT ;
    USE SIGNAL ;
    ANTENNADIFFAREA 0.702900 ;
    PORT
      LAYER met3 ;
        RECT 349.400 111.560 350.000 112.160 ;
    END
  END result[0]
  PIN result[10]
    DIRECTION OUTPUT ;
    USE SIGNAL ;
    ANTENNADIFFAREA 0.702900 ;
    PORT
      LAYER met3 ;
        RECT 349.400 70.760 350.000 71.360 ;
    END
  END result[10]
  PIN result[11]
    DIRECTION OUTPUT ;
    USE SIGNAL ;
    ANTENNADIFFAREA 0.702900 ;
    PORT
      LAYER met2 ;
        RECT 320.250 0.000 320.530 0.280 ;
    END
  END result[11]
  PIN result[12]
    DIRECTION OUTPUT ;
    USE SIGNAL ;
    ANTENNADIFFAREA 0.702900 ;
    PORT
      LAYER met2 ;
        RECT 266.890 0.000 267.170 0.280 ;
    END
  END result[12]
  PIN result[13]
    DIRECTION OUTPUT ;
    USE SIGNAL ;
    ANTENNADIFFAREA 0.702900 ;
    PORT
      LAYER met2 ;
        RECT 311.050 0.000 311.330 0.280 ;
    END
  END result[13]
  PIN result[14]
    DIRECTION OUTPUT ;
    USE SIGNAL ;
    ANTENNADIFFAREA 0.702900 ;
    PORT
      LAYER met2 ;
        RECT 193.290 0.000 193.570 0.280 ;
    END
  END result[14]
  PIN result[15]
    DIRECTION OUTPUT ;
    USE SIGNAL ;
    ANTENNADIFFAREA 0.702900 ;
    PORT
      LAYER met2 ;
        RECT 224.570 0.000 224.850 0.280 ;
    END
  END result[15]
  PIN result[16]
    DIRECTION OUTPUT ;
    USE SIGNAL ;
    ANTENNADIFFAREA 0.702900 ;
    PORT
      LAYER met2 ;
        RECT 263.210 0.000 263.490 0.280 ;
    END
  END result[16]
  PIN result[17]
    DIRECTION OUTPUT ;
    USE SIGNAL ;
    ANTENNADIFFAREA 0.702900 ;
    PORT
      LAYER met2 ;
        RECT 234.690 0.000 234.970 0.280 ;
    END
  END result[17]
  PIN result[18]
    DIRECTION OUTPUT ;
    USE SIGNAL ;
    ANTENNADIFFAREA 0.702900 ;
    PORT
      LAYER met2 ;
        RECT 177.650 0.000 177.930 0.280 ;
    END
  END result[18]
  PIN result[19]
    DIRECTION OUTPUT ;
    USE SIGNAL ;
    ANTENNADIFFAREA 0.702900 ;
    PORT
      LAYER met2 ;
        RECT 247.570 0.000 247.850 0.280 ;
    END
  END result[19]
  PIN result[1]
    DIRECTION OUTPUT ;
    USE SIGNAL ;
    ANTENNADIFFAREA 0.702900 ;
    PORT
      LAYER met3 ;
        RECT 349.400 78.920 350.000 79.520 ;
    END
  END result[1]
  PIN result[20]
    DIRECTION OUTPUT ;
    USE SIGNAL ;
    ANTENNADIFFAREA 0.702900 ;
    PORT
      LAYER met2 ;
        RECT 288.050 0.000 288.330 0.280 ;
    END
  END result[20]
  PIN result[21]
    DIRECTION OUTPUT ;
    USE SIGNAL ;
    ANTENNADIFFAREA 0.702900 ;
    PORT
      LAYER met2 ;
        RECT 268.730 0.000 269.010 0.280 ;
    END
  END result[21]
  PIN result[22]
    DIRECTION OUTPUT ;
    USE SIGNAL ;
    ANTENNADIFFAREA 0.702900 ;
    PORT
      LAYER met2 ;
        RECT 294.490 0.000 294.770 0.280 ;
    END
  END result[22]
  PIN result[23]
    DIRECTION OUTPUT ;
    USE SIGNAL ;
    ANTENNADIFFAREA 0.702900 ;
    PORT
      LAYER met2 ;
        RECT 300.010 0.000 300.290 0.280 ;
    END
  END result[23]
  PIN result[24]
    DIRECTION OUTPUT ;
    USE SIGNAL ;
    ANTENNADIFFAREA 0.702900 ;
    PORT
      LAYER met3 ;
        RECT 349.400 87.080 350.000 87.680 ;
    END
  END result[24]
  PIN result[25]
    DIRECTION OUTPUT ;
    USE SIGNAL ;
    ANTENNADIFFAREA 0.702900 ;
    PORT
      LAYER met2 ;
        RECT 279.770 0.000 280.050 0.280 ;
    END
  END result[25]
  PIN result[26]
    DIRECTION OUTPUT ;
    USE SIGNAL ;
    ANTENNADIFFAREA 0.702900 ;
    PORT
      LAYER met3 ;
        RECT 349.400 118.360 350.000 118.960 ;
    END
  END result[26]
  PIN result[27]
    DIRECTION OUTPUT ;
    USE SIGNAL ;
    ANTENNADIFFAREA 0.702900 ;
    PORT
      LAYER met3 ;
        RECT 349.400 110.200 350.000 110.800 ;
    END
  END result[27]
  PIN result[28]
    DIRECTION OUTPUT ;
    USE SIGNAL ;
    ANTENNADIFFAREA 0.702900 ;
    PORT
      LAYER met3 ;
        RECT 349.400 125.160 350.000 125.760 ;
    END
  END result[28]
  PIN result[29]
    DIRECTION OUTPUT ;
    USE SIGNAL ;
    ANTENNADIFFAREA 0.702900 ;
    PORT
      LAYER met3 ;
        RECT 349.400 312.840 350.000 313.440 ;
    END
  END result[29]
  PIN result[2]
    DIRECTION OUTPUT ;
    USE SIGNAL ;
    ANTENNADIFFAREA 0.702900 ;
    PORT
      LAYER met3 ;
        RECT 349.400 93.880 350.000 94.480 ;
    END
  END result[2]
  PIN result[30]
    DIRECTION OUTPUT ;
    USE SIGNAL ;
    ANTENNADIFFAREA 0.702900 ;
    PORT
      LAYER met3 ;
        RECT 349.400 138.760 350.000 139.360 ;
    END
  END result[30]
  PIN result[31]
    DIRECTION OUTPUT ;
    USE SIGNAL ;
    ANTENNADIFFAREA 0.702900 ;
    PORT
      LAYER met3 ;
        RECT 349.400 165.960 350.000 166.560 ;
    END
  END result[31]
  PIN result[32]
    DIRECTION OUTPUT ;
    USE SIGNAL ;
    ANTENNADIFFAREA 0.702900 ;
    PORT
      LAYER met3 ;
        RECT 349.400 144.200 350.000 144.800 ;
    END
  END result[32]
  PIN result[33]
    DIRECTION OUTPUT ;
    USE SIGNAL ;
    ANTENNADIFFAREA 0.702900 ;
    PORT
      LAYER met3 ;
        RECT 349.400 180.920 350.000 181.520 ;
    END
  END result[33]
  PIN result[34]
    DIRECTION OUTPUT ;
    USE SIGNAL ;
    ANTENNADIFFAREA 0.702900 ;
    PORT
      LAYER met3 ;
        RECT 349.400 198.600 350.000 199.200 ;
    END
  END result[34]
  PIN result[35]
    DIRECTION OUTPUT ;
    USE SIGNAL ;
    ANTENNADIFFAREA 0.702900 ;
    PORT
      LAYER met3 ;
        RECT 349.400 149.640 350.000 150.240 ;
    END
  END result[35]
  PIN result[36]
    DIRECTION OUTPUT ;
    USE SIGNAL ;
    ANTENNADIFFAREA 0.702900 ;
    PORT
      LAYER met3 ;
        RECT 349.400 174.120 350.000 174.720 ;
    END
  END result[36]
  PIN result[37]
    DIRECTION OUTPUT ;
    USE SIGNAL ;
    ANTENNADIFFAREA 0.702900 ;
    PORT
      LAYER met3 ;
        RECT 349.400 280.200 350.000 280.800 ;
    END
  END result[37]
  PIN result[38]
    DIRECTION OUTPUT ;
    USE SIGNAL ;
    ANTENNADIFFAREA 0.702900 ;
    PORT
      LAYER met3 ;
        RECT 349.400 208.120 350.000 208.720 ;
    END
  END result[38]
  PIN result[39]
    DIRECTION OUTPUT ;
    USE SIGNAL ;
    ANTENNADIFFAREA 0.702900 ;
    PORT
      LAYER met3 ;
        RECT 349.400 205.400 350.000 206.000 ;
    END
  END result[39]
  PIN result[3]
    DIRECTION OUTPUT ;
    USE SIGNAL ;
    ANTENNADIFFAREA 0.702900 ;
    PORT
      LAYER met3 ;
        RECT 349.400 92.520 350.000 93.120 ;
    END
  END result[3]
  PIN result[40]
    DIRECTION OUTPUT ;
    USE SIGNAL ;
    ANTENNADIFFAREA 0.702900 ;
    PORT
      LAYER met3 ;
        RECT 349.400 287.000 350.000 287.600 ;
    END
  END result[40]
  PIN result[41]
    DIRECTION OUTPUT ;
    USE SIGNAL ;
    ANTENNADIFFAREA 0.702900 ;
    PORT
      LAYER met3 ;
        RECT 349.400 219.000 350.000 219.600 ;
    END
  END result[41]
  PIN result[42]
    DIRECTION OUTPUT ;
    USE SIGNAL ;
    ANTENNADIFFAREA 0.702900 ;
    PORT
      LAYER met3 ;
        RECT 349.400 216.280 350.000 216.880 ;
    END
  END result[42]
  PIN result[43]
    DIRECTION OUTPUT ;
    USE SIGNAL ;
    ANTENNADIFFAREA 0.702900 ;
    PORT
      LAYER met3 ;
        RECT 349.400 278.840 350.000 279.440 ;
    END
  END result[43]
  PIN result[44]
    DIRECTION OUTPUT ;
    USE SIGNAL ;
    ANTENNADIFFAREA 0.702900 ;
    PORT
      LAYER met3 ;
        RECT 349.400 284.280 350.000 284.880 ;
    END
  END result[44]
  PIN result[45]
    DIRECTION OUTPUT ;
    USE SIGNAL ;
    ANTENNADIFFAREA 0.702900 ;
    PORT
      LAYER met3 ;
        RECT 349.400 295.160 350.000 295.760 ;
    END
  END result[45]
  PIN result[46]
    DIRECTION OUTPUT ;
    USE SIGNAL ;
    ANTENNADIFFAREA 0.702900 ;
    PORT
      LAYER met3 ;
        RECT 349.400 293.800 350.000 294.400 ;
    END
  END result[46]
  PIN result[47]
    DIRECTION OUTPUT ;
    USE SIGNAL ;
    ANTENNADIFFAREA 0.702900 ;
    PORT
      LAYER met3 ;
        RECT 349.400 288.360 350.000 288.960 ;
    END
  END result[47]
  PIN result[48]
    DIRECTION OUTPUT ;
    USE SIGNAL ;
    ANTENNADIFFAREA 0.702900 ;
    PORT
      LAYER met3 ;
        RECT 349.400 303.320 350.000 303.920 ;
    END
  END result[48]
  PIN result[49]
    DIRECTION OUTPUT ;
    USE SIGNAL ;
    ANTENNADIFFAREA 0.702900 ;
    PORT
      LAYER met3 ;
        RECT 349.400 297.880 350.000 298.480 ;
    END
  END result[49]
  PIN result[4]
    DIRECTION OUTPUT ;
    USE SIGNAL ;
    ANTENNADIFFAREA 0.702900 ;
    PORT
      LAYER met3 ;
        RECT 349.400 85.720 350.000 86.320 ;
    END
  END result[4]
  PIN result[50]
    DIRECTION OUTPUT ;
    USE SIGNAL ;
    ANTENNADIFFAREA 0.702900 ;
    PORT
      LAYER met3 ;
        RECT 349.400 76.200 350.000 76.800 ;
    END
  END result[50]
  PIN result[51]
    DIRECTION OUTPUT ;
    USE SIGNAL ;
    ANTENNADIFFAREA 0.702900 ;
    PORT
      LAYER met2 ;
        RECT 254.010 349.720 254.290 350.000 ;
    END
  END result[51]
  PIN result[52]
    DIRECTION OUTPUT ;
    USE SIGNAL ;
    ANTENNADIFFAREA 0.702900 ;
    PORT
      LAYER met2 ;
        RECT 244.810 349.720 245.090 350.000 ;
    END
  END result[52]
  PIN result[53]
    DIRECTION OUTPUT ;
    USE SIGNAL ;
    ANTENNADIFFAREA 0.702900 ;
    PORT
      LAYER met3 ;
        RECT 349.400 304.680 350.000 305.280 ;
    END
  END result[53]
  PIN result[54]
    DIRECTION OUTPUT ;
    USE SIGNAL ;
    ANTENNADIFFAREA 0.702900 ;
    PORT
      LAYER met2 ;
        RECT 253.090 349.720 253.370 350.000 ;
    END
  END result[54]
  PIN result[55]
    DIRECTION OUTPUT ;
    USE SIGNAL ;
    ANTENNADIFFAREA 0.702900 ;
    PORT
      LAYER met2 ;
        RECT 249.410 349.720 249.690 350.000 ;
    END
  END result[55]
  PIN result[56]
    DIRECTION OUTPUT ;
    USE SIGNAL ;
    ANTENNADIFFAREA 0.702900 ;
    PORT
      LAYER met3 ;
        RECT 349.400 318.280 350.000 318.880 ;
    END
  END result[56]
  PIN result[57]
    DIRECTION OUTPUT ;
    USE SIGNAL ;
    ANTENNADIFFAREA 0.702900 ;
    PORT
      LAYER met2 ;
        RECT 279.770 349.720 280.050 350.000 ;
    END
  END result[57]
  PIN result[58]
    DIRECTION OUTPUT ;
    USE SIGNAL ;
    ANTENNADIFFAREA 0.702900 ;
    PORT
      LAYER met2 ;
        RECT 289.890 349.720 290.170 350.000 ;
    END
  END result[58]
  PIN result[59]
    DIRECTION OUTPUT ;
    USE SIGNAL ;
    ANTENNADIFFAREA 0.702900 ;
    PORT
      LAYER met2 ;
        RECT 287.130 349.720 287.410 350.000 ;
    END
  END result[59]
  PIN result[5]
    DIRECTION OUTPUT ;
    USE SIGNAL ;
    ANTENNADIFFAREA 0.702900 ;
    PORT
      LAYER met3 ;
        RECT 349.400 99.320 350.000 99.920 ;
    END
  END result[5]
  PIN result[60]
    DIRECTION OUTPUT ;
    USE SIGNAL ;
    ANTENNADIFFAREA 0.702900 ;
    PORT
      LAYER met2 ;
        RECT 265.050 349.720 265.330 350.000 ;
    END
  END result[60]
  PIN result[61]
    DIRECTION OUTPUT ;
    USE SIGNAL ;
    ANTENNADIFFAREA 0.702900 ;
    PORT
      LAYER met2 ;
        RECT 266.890 349.720 267.170 350.000 ;
    END
  END result[61]
  PIN result[62]
    DIRECTION OUTPUT ;
    USE SIGNAL ;
    ANTENNADIFFAREA 0.702900 ;
    PORT
      LAYER met3 ;
        RECT 349.400 273.400 350.000 274.000 ;
    END
  END result[62]
  PIN result[63]
    DIRECTION OUTPUT ;
    USE SIGNAL ;
    ANTENNADIFFAREA 0.702900 ;
    PORT
      LAYER met3 ;
        RECT 349.400 281.560 350.000 282.160 ;
    END
  END result[63]
  PIN result[6]
    DIRECTION OUTPUT ;
    USE SIGNAL ;
    ANTENNADIFFAREA 0.702900 ;
    PORT
      LAYER met3 ;
        RECT 349.400 66.680 350.000 67.280 ;
    END
  END result[6]
  PIN result[7]
    DIRECTION OUTPUT ;
    USE SIGNAL ;
    ANTENNADIFFAREA 0.702900 ;
    PORT
      LAYER met3 ;
        RECT 349.400 102.040 350.000 102.640 ;
    END
  END result[7]
  PIN result[8]
    DIRECTION OUTPUT ;
    USE SIGNAL ;
    ANTENNADIFFAREA 0.702900 ;
    PORT
      LAYER met2 ;
        RECT 312.890 0.000 313.170 0.280 ;
    END
  END result[8]
  PIN result[9]
    DIRECTION OUTPUT ;
    USE SIGNAL ;
    ANTENNADIFFAREA 0.702900 ;
    PORT
      LAYER met3 ;
        RECT 349.400 59.880 350.000 60.480 ;
    END
  END result[9]
  PIN rst_n
    DIRECTION INPUT ;
    USE SIGNAL ;
    ANTENNAGATEAREA 0.742500 ;
    PORT
      LAYER met3 ;
        RECT 0.000 331.880 0.600 332.480 ;
    END
  END rst_n
  PIN valid_in
    DIRECTION INPUT ;
    USE SIGNAL ;
    ANTENNAGATEAREA 0.213000 ;
    PORT
      LAYER met3 ;
        RECT 0.000 23.160 0.600 23.760 ;
    END
  END valid_in
  PIN valid_out
    DIRECTION OUTPUT ;
    USE SIGNAL ;
    ANTENNADIFFAREA 0.702900 ;
    PORT
      LAYER met2 ;
        RECT 64.490 0.000 64.770 0.280 ;
    END
  END valid_out
  PIN zero_flag
    DIRECTION OUTPUT ;
    USE SIGNAL ;
    ANTENNADIFFAREA 0.702900 ;
    PORT
      LAYER met3 ;
        RECT 349.400 289.720 350.000 290.320 ;
    END
  END zero_flag
  OBS
      LAYER nwell ;
        RECT 5.330 10.795 344.270 337.365 ;
      LAYER li1 ;
        RECT 5.520 10.795 344.080 337.365 ;
      LAYER met1 ;
        RECT 0.990 10.640 349.070 337.520 ;
      LAYER met2 ;
        RECT 1.010 349.440 34.770 349.720 ;
        RECT 35.610 349.440 40.290 349.720 ;
        RECT 41.130 349.440 41.210 349.720 ;
        RECT 42.050 349.440 51.330 349.720 ;
        RECT 52.170 349.440 52.250 349.720 ;
        RECT 53.090 349.440 54.090 349.720 ;
        RECT 54.930 349.440 57.770 349.720 ;
        RECT 58.610 349.440 60.530 349.720 ;
        RECT 61.370 349.440 68.810 349.720 ;
        RECT 69.650 349.440 71.570 349.720 ;
        RECT 72.410 349.440 78.010 349.720 ;
        RECT 78.850 349.440 79.850 349.720 ;
        RECT 80.690 349.440 87.210 349.720 ;
        RECT 88.050 349.440 91.810 349.720 ;
        RECT 92.650 349.440 93.650 349.720 ;
        RECT 94.490 349.440 94.570 349.720 ;
        RECT 95.410 349.440 95.490 349.720 ;
        RECT 96.330 349.440 100.090 349.720 ;
        RECT 100.930 349.440 101.010 349.720 ;
        RECT 101.850 349.440 101.930 349.720 ;
        RECT 102.770 349.440 102.850 349.720 ;
        RECT 103.690 349.440 106.530 349.720 ;
        RECT 107.370 349.440 113.890 349.720 ;
        RECT 114.730 349.440 117.570 349.720 ;
        RECT 118.410 349.440 121.250 349.720 ;
        RECT 122.090 349.440 135.970 349.720 ;
        RECT 136.810 349.440 139.650 349.720 ;
        RECT 140.490 349.440 161.730 349.720 ;
        RECT 162.570 349.440 175.530 349.720 ;
        RECT 176.370 349.440 188.410 349.720 ;
        RECT 189.250 349.440 190.250 349.720 ;
        RECT 191.090 349.440 204.050 349.720 ;
        RECT 204.890 349.440 204.970 349.720 ;
        RECT 205.810 349.440 216.010 349.720 ;
        RECT 216.850 349.440 219.690 349.720 ;
        RECT 220.530 349.440 239.010 349.720 ;
        RECT 239.850 349.440 244.530 349.720 ;
        RECT 245.370 349.440 249.130 349.720 ;
        RECT 249.970 349.440 252.810 349.720 ;
        RECT 253.650 349.440 253.730 349.720 ;
        RECT 254.570 349.440 264.770 349.720 ;
        RECT 265.610 349.440 266.610 349.720 ;
        RECT 267.450 349.440 278.570 349.720 ;
        RECT 279.410 349.440 279.490 349.720 ;
        RECT 280.330 349.440 286.850 349.720 ;
        RECT 287.690 349.440 289.610 349.720 ;
        RECT 290.450 349.440 349.050 349.720 ;
        RECT 1.010 0.560 349.050 349.440 ;
        RECT 1.010 0.280 64.210 0.560 ;
        RECT 65.050 0.280 68.810 0.560 ;
        RECT 69.650 0.280 75.250 0.560 ;
        RECT 76.090 0.280 82.610 0.560 ;
        RECT 83.450 0.280 84.450 0.560 ;
        RECT 85.290 0.280 85.370 0.560 ;
        RECT 86.210 0.280 87.210 0.560 ;
        RECT 88.050 0.280 88.130 0.560 ;
        RECT 88.970 0.280 94.570 0.560 ;
        RECT 95.410 0.280 97.330 0.560 ;
        RECT 98.170 0.280 98.250 0.560 ;
        RECT 99.090 0.280 112.050 0.560 ;
        RECT 112.890 0.280 118.490 0.560 ;
        RECT 119.330 0.280 132.290 0.560 ;
        RECT 133.130 0.280 144.250 0.560 ;
        RECT 145.090 0.280 148.850 0.560 ;
        RECT 149.690 0.280 152.530 0.560 ;
        RECT 153.370 0.280 173.690 0.560 ;
        RECT 174.530 0.280 177.370 0.560 ;
        RECT 178.210 0.280 193.010 0.560 ;
        RECT 193.850 0.280 193.930 0.560 ;
        RECT 194.770 0.280 216.930 0.560 ;
        RECT 217.770 0.280 224.290 0.560 ;
        RECT 225.130 0.280 234.410 0.560 ;
        RECT 235.250 0.280 240.850 0.560 ;
        RECT 241.690 0.280 247.290 0.560 ;
        RECT 248.130 0.280 255.570 0.560 ;
        RECT 256.410 0.280 262.930 0.560 ;
        RECT 263.770 0.280 266.610 0.560 ;
        RECT 267.450 0.280 267.530 0.560 ;
        RECT 268.370 0.280 268.450 0.560 ;
        RECT 269.290 0.280 273.970 0.560 ;
        RECT 274.810 0.280 278.570 0.560 ;
        RECT 279.410 0.280 279.490 0.560 ;
        RECT 280.330 0.280 282.250 0.560 ;
        RECT 283.090 0.280 287.770 0.560 ;
        RECT 288.610 0.280 294.210 0.560 ;
        RECT 295.050 0.280 299.730 0.560 ;
        RECT 300.570 0.280 310.770 0.560 ;
        RECT 311.610 0.280 312.610 0.560 ;
        RECT 313.450 0.280 319.970 0.560 ;
        RECT 320.810 0.280 349.050 0.560 ;
      LAYER met3 ;
        RECT 0.600 334.240 349.400 337.445 ;
        RECT 1.000 331.480 349.400 334.240 ;
        RECT 0.600 319.280 349.400 331.480 ;
        RECT 0.600 317.880 349.000 319.280 ;
        RECT 0.600 313.840 349.400 317.880 ;
        RECT 0.600 312.440 349.000 313.840 ;
        RECT 0.600 305.680 349.400 312.440 ;
        RECT 0.600 302.920 349.000 305.680 ;
        RECT 0.600 298.880 349.400 302.920 ;
        RECT 0.600 296.160 349.000 298.880 ;
        RECT 1.000 294.760 349.000 296.160 ;
        RECT 0.600 286.640 349.000 294.760 ;
        RECT 1.000 285.240 349.000 286.640 ;
        RECT 0.600 278.480 349.000 285.240 ;
        RECT 1.000 274.360 349.000 278.480 ;
        RECT 0.600 273.000 349.000 274.360 ;
        RECT 0.600 266.240 349.400 273.000 ;
        RECT 1.000 263.480 349.400 266.240 ;
        RECT 0.600 258.080 349.400 263.480 ;
        RECT 1.000 255.320 349.400 258.080 ;
        RECT 0.600 249.920 349.400 255.320 ;
        RECT 1.000 248.520 349.400 249.920 ;
        RECT 0.600 244.480 349.400 248.520 ;
        RECT 1.000 243.080 349.400 244.480 ;
        RECT 0.600 236.320 349.400 243.080 ;
        RECT 1.000 234.920 349.400 236.320 ;
        RECT 0.600 225.440 349.400 234.920 ;
        RECT 1.000 224.040 349.400 225.440 ;
        RECT 0.600 220.000 349.400 224.040 ;
        RECT 0.600 218.600 349.000 220.000 ;
        RECT 0.600 217.280 349.400 218.600 ;
        RECT 0.600 215.880 349.000 217.280 ;
        RECT 0.600 209.120 349.400 215.880 ;
        RECT 0.600 207.720 349.000 209.120 ;
        RECT 0.600 206.400 349.400 207.720 ;
        RECT 1.000 205.000 349.000 206.400 ;
        RECT 0.600 200.960 349.400 205.000 ;
        RECT 0.600 198.200 349.000 200.960 ;
        RECT 0.600 196.880 349.400 198.200 ;
        RECT 0.600 195.480 349.000 196.880 ;
        RECT 0.600 188.720 349.400 195.480 ;
        RECT 0.600 186.000 349.000 188.720 ;
        RECT 1.000 184.600 349.000 186.000 ;
        RECT 0.600 183.280 349.400 184.600 ;
        RECT 0.600 180.520 349.000 183.280 ;
        RECT 0.600 176.480 349.400 180.520 ;
        RECT 1.000 175.120 349.400 176.480 ;
        RECT 1.000 175.080 349.000 175.120 ;
        RECT 0.600 173.720 349.000 175.080 ;
        RECT 0.600 166.960 349.400 173.720 ;
        RECT 0.600 165.600 349.000 166.960 ;
        RECT 1.000 165.560 349.000 165.600 ;
        RECT 1.000 164.200 349.400 165.560 ;
        RECT 0.600 160.160 349.400 164.200 ;
        RECT 0.600 158.760 349.000 160.160 ;
        RECT 0.600 157.440 349.400 158.760 ;
        RECT 0.600 156.080 349.000 157.440 ;
        RECT 1.000 156.040 349.000 156.080 ;
        RECT 1.000 154.720 349.400 156.040 ;
        RECT 1.000 154.680 349.000 154.720 ;
        RECT 0.600 153.320 349.000 154.680 ;
        RECT 0.600 150.640 349.400 153.320 ;
        RECT 0.600 149.240 349.000 150.640 ;
        RECT 0.600 146.560 349.400 149.240 ;
        RECT 1.000 145.200 349.400 146.560 ;
        RECT 1.000 145.160 349.000 145.200 ;
        RECT 0.600 143.800 349.000 145.160 ;
        RECT 0.600 142.480 349.400 143.800 ;
        RECT 0.600 141.080 349.000 142.480 ;
        RECT 0.600 139.760 349.400 141.080 ;
        RECT 0.600 138.360 349.000 139.760 ;
        RECT 0.600 137.040 349.400 138.360 ;
        RECT 1.000 135.680 349.400 137.040 ;
        RECT 1.000 135.640 349.000 135.680 ;
        RECT 0.600 131.560 349.000 135.640 ;
        RECT 0.600 128.880 349.400 131.560 ;
        RECT 0.600 127.520 349.000 128.880 ;
        RECT 1.000 127.480 349.000 127.520 ;
        RECT 1.000 126.160 349.400 127.480 ;
        RECT 1.000 126.120 349.000 126.160 ;
        RECT 0.600 123.400 349.000 126.120 ;
        RECT 0.600 119.360 349.400 123.400 ;
        RECT 0.600 116.600 349.000 119.360 ;
        RECT 0.600 112.560 349.400 116.600 ;
        RECT 0.600 109.800 349.000 112.560 ;
        RECT 0.600 103.040 349.400 109.800 ;
        RECT 0.600 101.640 349.000 103.040 ;
        RECT 0.600 100.320 349.400 101.640 ;
        RECT 0.600 98.920 349.000 100.320 ;
        RECT 0.600 94.880 349.400 98.920 ;
        RECT 0.600 92.120 349.000 94.880 ;
        RECT 0.600 88.080 349.400 92.120 ;
        RECT 0.600 83.960 349.000 88.080 ;
        RECT 0.600 79.920 349.400 83.960 ;
        RECT 0.600 78.520 349.000 79.920 ;
        RECT 0.600 77.200 349.400 78.520 ;
        RECT 0.600 75.840 349.000 77.200 ;
        RECT 1.000 75.800 349.000 75.840 ;
        RECT 1.000 71.760 349.400 75.800 ;
        RECT 1.000 70.360 349.000 71.760 ;
        RECT 1.000 67.680 349.400 70.360 ;
        RECT 1.000 66.280 349.000 67.680 ;
        RECT 1.000 60.880 349.400 66.280 ;
        RECT 1.000 59.480 349.000 60.880 ;
        RECT 1.000 41.800 349.400 59.480 ;
        RECT 0.600 39.120 349.400 41.800 ;
        RECT 1.000 36.360 349.400 39.120 ;
        RECT 0.600 35.040 349.400 36.360 ;
        RECT 1.000 33.640 349.400 35.040 ;
        RECT 0.600 24.160 349.400 33.640 ;
        RECT 1.000 22.760 349.400 24.160 ;
        RECT 0.600 10.715 349.400 22.760 ;
      LAYER met4 ;
        RECT 13.175 32.135 20.640 311.265 ;
        RECT 23.040 32.135 23.940 311.265 ;
        RECT 26.340 32.135 174.240 311.265 ;
        RECT 176.640 32.135 177.540 311.265 ;
        RECT 179.940 32.135 317.105 311.265 ;
  END
END alu64_cp_top
END LIBRARY

